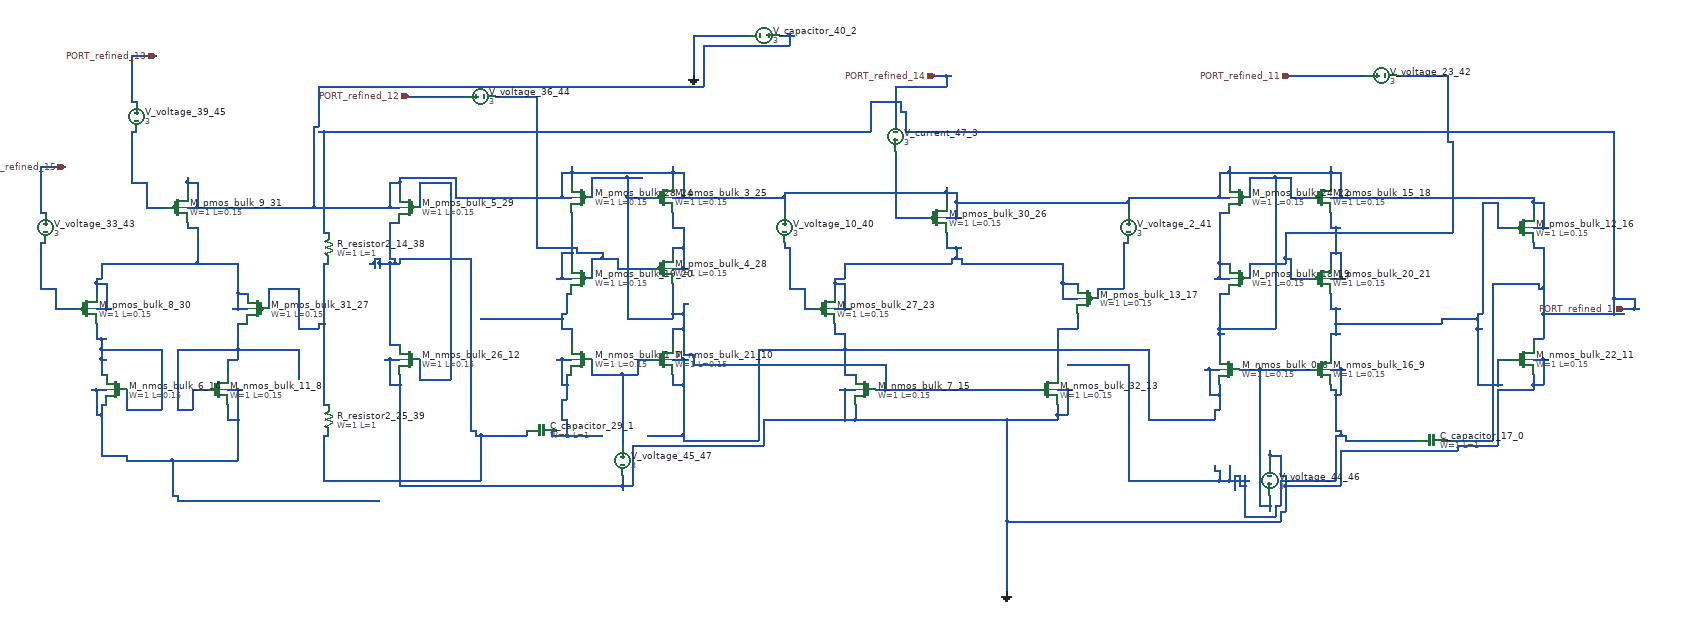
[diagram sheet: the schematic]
v {xschem version=3.4.8 file_version=1.2}
G {}
K {}
V {}
S {}
E {}
C {sky130_fd_pr/cap_mim_m3_1.sym} 2800 1020 1 0 {name="C_capacitor_17_0" model=cap_mim_m3_1 W=1 L=1 MF=1 spiceprefix=X}
C {sky130_fd_pr/cap_mim_m3_1.sym} 1040 1000 1 0 {name="C_capacitor_29_1" model=cap_mim_m3_1 W=1 L=1 MF=1 spiceprefix=X}
C {devices/vsource.sym} 1480 220 1 0 {name="V_capacitor_40_2" value=3 savecurrent=false}
C {devices/vsource.sym} 1740 420 2 0 {name="V_current_47_3" value=3 savecurrent=false}
C {devices/gnd.sym} 1960 1320 0 0 {name="l_gnd_37_4" lab="GND"}
C {devices/gnd.sym} 1340 300 0 0 {name="l_gnd_38_5" lab="GND"}
C {sky130_fd_pr/nfet_01v8.sym} 2400 880 0 1 {name="M_nmos_bulk_0_6"
W=1
L=0.15
nf=1 
mult=1
ad="expr('int((@nf + 1)/2) * @W / @nf * 0.29')"
pd="expr('2*int((@nf + 1)/2) * (@W / @nf + 0.29)')"
as="expr('int((@nf + 2)/2) * @W / @nf * 0.29')"
ps="expr('2*int((@nf + 2)/2) * (@W / @nf + 0.29)')"
nrd="expr('0.29 / @W ')" nrs="expr('0.29 / @W ')"
sa=0 sb=0 sd=0
model=nfet_01v8
spiceprefix=X
}
C {sky130_fd_pr/nfet_01v8.sym} 1120 860 0 1 {name="M_nmos_bulk_1_7"
W=1
L=0.15
nf=1 
mult=1
ad="expr('int((@nf + 1)/2) * @W / @nf * 0.29')"
pd="expr('2*int((@nf + 1)/2) * (@W / @nf + 0.29)')"
as="expr('int((@nf + 2)/2) * @W / @nf * 0.29')"
ps="expr('2*int((@nf + 2)/2) * (@W / @nf + 0.29)')"
nrd="expr('0.29 / @W ')" nrs="expr('0.29 / @W ')"
sa=0 sb=0 sd=0
model=nfet_01v8
spiceprefix=X
}
C {sky130_fd_pr/nfet_01v8.sym} 400 920 0 0 {name="M_nmos_bulk_11_8"
W=1
L=0.15
nf=1 
mult=1
ad="expr('int((@nf + 1)/2) * @W / @nf * 0.29')"
pd="expr('2*int((@nf + 1)/2) * (@W / @nf + 0.29)')"
as="expr('int((@nf + 2)/2) * @W / @nf * 0.29')"
ps="expr('2*int((@nf + 2)/2) * (@W / @nf + 0.29)')"
nrd="expr('0.29 / @W ')" nrs="expr('0.29 / @W ')"
sa=0 sb=0 sd=0
model=nfet_01v8
spiceprefix=X
}
C {sky130_fd_pr/nfet_01v8.sym} 2580 880 0 0 {name="M_nmos_bulk_16_9"
W=1
L=0.15
nf=1 
mult=1
ad="expr('int((@nf + 1)/2) * @W / @nf * 0.29')"
pd="expr('2*int((@nf + 1)/2) * (@W / @nf + 0.29)')"
as="expr('int((@nf + 2)/2) * @W / @nf * 0.29')"
ps="expr('2*int((@nf + 2)/2) * (@W / @nf + 0.29)')"
nrd="expr('0.29 / @W ')" nrs="expr('0.29 / @W ')"
sa=0 sb=0 sd=0
model=nfet_01v8
spiceprefix=X
}
C {sky130_fd_pr/nfet_01v8.sym} 1280 860 0 0 {name="M_nmos_bulk_21_10"
W=1
L=0.15
nf=1 
mult=1
ad="expr('int((@nf + 1)/2) * @W / @nf * 0.29')"
pd="expr('2*int((@nf + 1)/2) * (@W / @nf + 0.29)')"
as="expr('int((@nf + 2)/2) * @W / @nf * 0.29')"
ps="expr('2*int((@nf + 2)/2) * (@W / @nf + 0.29)')"
nrd="expr('0.29 / @W ')" nrs="expr('0.29 / @W ')"
sa=0 sb=0 sd=0
model=nfet_01v8
spiceprefix=X
}
C {sky130_fd_pr/nfet_01v8.sym} 2980 860 0 0 {name="M_nmos_bulk_22_11"
W=1
L=0.15
nf=1 
mult=1
ad="expr('int((@nf + 1)/2) * @W / @nf * 0.29')"
pd="expr('2*int((@nf + 1)/2) * (@W / @nf + 0.29)')"
as="expr('int((@nf + 2)/2) * @W / @nf * 0.29')"
ps="expr('2*int((@nf + 2)/2) * (@W / @nf + 0.29)')"
nrd="expr('0.29 / @W ')" nrs="expr('0.29 / @W ')"
sa=0 sb=0 sd=0
model=nfet_01v8
spiceprefix=X
}
C {sky130_fd_pr/nfet_01v8.sym} 780 860 0 1 {name="M_nmos_bulk_26_12"
W=1
L=0.15
nf=1 
mult=1
ad="expr('int((@nf + 1)/2) * @W / @nf * 0.29')"
pd="expr('2*int((@nf + 1)/2) * (@W / @nf + 0.29)')"
as="expr('int((@nf + 2)/2) * @W / @nf * 0.29')"
ps="expr('2*int((@nf + 2)/2) * (@W / @nf + 0.29)')"
nrd="expr('0.29 / @W ')" nrs="expr('0.29 / @W ')"
sa=0 sb=0 sd=0
model=nfet_01v8
spiceprefix=X
}
C {sky130_fd_pr/nfet_01v8.sym} 2040 920 0 0 {name="M_nmos_bulk_32_13"
W=1
L=0.15
nf=1 
mult=1
ad="expr('int((@nf + 1)/2) * @W / @nf * 0.29')"
pd="expr('2*int((@nf + 1)/2) * (@W / @nf + 0.29)')"
as="expr('int((@nf + 2)/2) * @W / @nf * 0.29')"
ps="expr('2*int((@nf + 2)/2) * (@W / @nf + 0.29)')"
nrd="expr('0.29 / @W ')" nrs="expr('0.29 / @W ')"
sa=0 sb=0 sd=0
model=nfet_01v8
spiceprefix=X
}
C {sky130_fd_pr/nfet_01v8.sym} 200 920 0 1 {name="M_nmos_bulk_6_14"
W=1
L=0.15
nf=1 
mult=1
ad="expr('int((@nf + 1)/2) * @W / @nf * 0.29')"
pd="expr('2*int((@nf + 1)/2) * (@W / @nf + 0.29)')"
as="expr('int((@nf + 2)/2) * @W / @nf * 0.29')"
ps="expr('2*int((@nf + 2)/2) * (@W / @nf + 0.29)')"
nrd="expr('0.29 / @W ')" nrs="expr('0.29 / @W ')"
sa=0 sb=0 sd=0
model=nfet_01v8
spiceprefix=X
}
C {sky130_fd_pr/nfet_01v8.sym} 1680 920 0 1 {name="M_nmos_bulk_7_15"
W=1
L=0.15
nf=1 
mult=1
ad="expr('int((@nf + 1)/2) * @W / @nf * 0.29')"
pd="expr('2*int((@nf + 1)/2) * (@W / @nf + 0.29)')"
as="expr('int((@nf + 2)/2) * @W / @nf * 0.29')"
ps="expr('2*int((@nf + 2)/2) * (@W / @nf + 0.29)')"
nrd="expr('0.29 / @W ')" nrs="expr('0.29 / @W ')"
sa=0 sb=0 sd=0
model=nfet_01v8
spiceprefix=X
}
C {sky130_fd_pr/pfet_01v8.sym} 2980 600 0 0 {name="M_pmos_bulk_12_16"
W=1
L=0.15
nf=1
mult=1
ad="expr('int((@nf + 1)/2) * @W / @nf * 0.29')"
pd="expr('2*int((@nf + 1)/2) * (@W / @nf + 0.29)')"
as="expr('int((@nf + 2)/2) * @W / @nf * 0.29')"
ps="expr('2*int((@nf + 2)/2) * (@W / @nf + 0.29)')"
nrd="expr('0.29 / @W ')" nrs="expr('0.29 / @W ')"
sa=0 sb=0 sd=0
model=pfet_01v8
spiceprefix=X
}
C {sky130_fd_pr/pfet_01v8.sym} 2120 740 0 1 {name="M_pmos_bulk_13_17"
W=1
L=0.15
nf=1
mult=1
ad="expr('int((@nf + 1)/2) * @W / @nf * 0.29')"
pd="expr('2*int((@nf + 1)/2) * (@W / @nf + 0.29)')"
as="expr('int((@nf + 2)/2) * @W / @nf * 0.29')"
ps="expr('2*int((@nf + 2)/2) * (@W / @nf + 0.29)')"
nrd="expr('0.29 / @W ')" nrs="expr('0.29 / @W ')"
sa=0 sb=0 sd=0
model=pfet_01v8
spiceprefix=X
}
C {sky130_fd_pr/pfet_01v8.sym} 2580 540 0 0 {name="M_pmos_bulk_15_18"
W=1
L=0.15
nf=1
mult=1
ad="expr('int((@nf + 1)/2) * @W / @nf * 0.29')"
pd="expr('2*int((@nf + 1)/2) * (@W / @nf + 0.29)')"
as="expr('int((@nf + 2)/2) * @W / @nf * 0.29')"
ps="expr('2*int((@nf + 2)/2) * (@W / @nf + 0.29)')"
nrd="expr('0.29 / @W ')" nrs="expr('0.29 / @W ')"
sa=0 sb=0 sd=0
model=pfet_01v8
spiceprefix=X
}
C {sky130_fd_pr/pfet_01v8.sym} 2420 700 0 1 {name="M_pmos_bulk_18_19"
W=1
L=0.15
nf=1
mult=1
ad="expr('int((@nf + 1)/2) * @W / @nf * 0.29')"
pd="expr('2*int((@nf + 1)/2) * (@W / @nf + 0.29)')"
as="expr('int((@nf + 2)/2) * @W / @nf * 0.29')"
ps="expr('2*int((@nf + 2)/2) * (@W / @nf + 0.29)')"
nrd="expr('0.29 / @W ')" nrs="expr('0.29 / @W ')"
sa=0 sb=0 sd=0
model=pfet_01v8
spiceprefix=X
}
C {sky130_fd_pr/pfet_01v8.sym} 1120 700 0 1 {name="M_pmos_bulk_19_20"
W=1
L=0.15
nf=1
mult=1
ad="expr('int((@nf + 1)/2) * @W / @nf * 0.29')"
pd="expr('2*int((@nf + 1)/2) * (@W / @nf + 0.29)')"
as="expr('int((@nf + 2)/2) * @W / @nf * 0.29')"
ps="expr('2*int((@nf + 2)/2) * (@W / @nf + 0.29)')"
nrd="expr('0.29 / @W ')" nrs="expr('0.29 / @W ')"
sa=0 sb=0 sd=0
model=pfet_01v8
spiceprefix=X
}
C {sky130_fd_pr/pfet_01v8.sym} 2580 700 0 0 {name="M_pmos_bulk_20_21"
W=1
L=0.15
nf=1
mult=1
ad="expr('int((@nf + 1)/2) * @W / @nf * 0.29')"
pd="expr('2*int((@nf + 1)/2) * (@W / @nf + 0.29)')"
as="expr('int((@nf + 2)/2) * @W / @nf * 0.29')"
ps="expr('2*int((@nf + 2)/2) * (@W / @nf + 0.29)')"
nrd="expr('0.29 / @W ')" nrs="expr('0.29 / @W ')"
sa=0 sb=0 sd=0
model=pfet_01v8
spiceprefix=X
}
C {sky130_fd_pr/pfet_01v8.sym} 2420 540 0 1 {name="M_pmos_bulk_24_22"
W=1
L=0.15
nf=1
mult=1
ad="expr('int((@nf + 1)/2) * @W / @nf * 0.29')"
pd="expr('2*int((@nf + 1)/2) * (@W / @nf + 0.29)')"
as="expr('int((@nf + 2)/2) * @W / @nf * 0.29')"
ps="expr('2*int((@nf + 2)/2) * (@W / @nf + 0.29)')"
nrd="expr('0.29 / @W ')" nrs="expr('0.29 / @W ')"
sa=0 sb=0 sd=0
model=pfet_01v8
spiceprefix=X
}
C {sky130_fd_pr/pfet_01v8.sym} 1600 760 0 0 {name="M_pmos_bulk_27_23"
W=1
L=0.15
nf=1
mult=1
ad="expr('int((@nf + 1)/2) * @W / @nf * 0.29')"
pd="expr('2*int((@nf + 1)/2) * (@W / @nf + 0.29)')"
as="expr('int((@nf + 2)/2) * @W / @nf * 0.29')"
ps="expr('2*int((@nf + 2)/2) * (@W / @nf + 0.29)')"
nrd="expr('0.29 / @W ')" nrs="expr('0.29 / @W ')"
sa=0 sb=0 sd=0
model=pfet_01v8
spiceprefix=X
}
C {sky130_fd_pr/pfet_01v8.sym} 1120 540 0 1 {name="M_pmos_bulk_28_24"
W=1
L=0.15
nf=1
mult=1
ad="expr('int((@nf + 1)/2) * @W / @nf * 0.29')"
pd="expr('2*int((@nf + 1)/2) * (@W / @nf + 0.29)')"
as="expr('int((@nf + 2)/2) * @W / @nf * 0.29')"
ps="expr('2*int((@nf + 2)/2) * (@W / @nf + 0.29)')"
nrd="expr('0.29 / @W ')" nrs="expr('0.29 / @W ')"
sa=0 sb=0 sd=0
model=pfet_01v8
spiceprefix=X
}
C {sky130_fd_pr/pfet_01v8.sym} 1280 540 0 0 {name="M_pmos_bulk_3_25"
W=1
L=0.15
nf=1
mult=1
ad="expr('int((@nf + 1)/2) * @W / @nf * 0.29')"
pd="expr('2*int((@nf + 1)/2) * (@W / @nf + 0.29)')"
as="expr('int((@nf + 2)/2) * @W / @nf * 0.29')"
ps="expr('2*int((@nf + 2)/2) * (@W / @nf + 0.29)')"
nrd="expr('0.29 / @W ')" nrs="expr('0.29 / @W ')"
sa=0 sb=0 sd=0
model=pfet_01v8
spiceprefix=X
}
C {sky130_fd_pr/pfet_01v8.sym} 1820 580 0 0 {name="M_pmos_bulk_30_26"
W=1
L=0.15
nf=1
mult=1
ad="expr('int((@nf + 1)/2) * @W / @nf * 0.29')"
pd="expr('2*int((@nf + 1)/2) * (@W / @nf + 0.29)')"
as="expr('int((@nf + 2)/2) * @W / @nf * 0.29')"
ps="expr('2*int((@nf + 2)/2) * (@W / @nf + 0.29)')"
nrd="expr('0.29 / @W ')" nrs="expr('0.29 / @W ')"
sa=0 sb=0 sd=0
model=pfet_01v8
spiceprefix=X
}
C {sky130_fd_pr/pfet_01v8.sym} 480 760 0 1 {name="M_pmos_bulk_31_27"
W=1
L=0.15
nf=1
mult=1
ad="expr('int((@nf + 1)/2) * @W / @nf * 0.29')"
pd="expr('2*int((@nf + 1)/2) * (@W / @nf + 0.29)')"
as="expr('int((@nf + 2)/2) * @W / @nf * 0.29')"
ps="expr('2*int((@nf + 2)/2) * (@W / @nf + 0.29)')"
nrd="expr('0.29 / @W ')" nrs="expr('0.29 / @W ')"
sa=0 sb=0 sd=0
model=pfet_01v8
spiceprefix=X
}
C {sky130_fd_pr/pfet_01v8.sym} 1280 680 0 0 {name="M_pmos_bulk_4_28"
W=1
L=0.15
nf=1
mult=1
ad="expr('int((@nf + 1)/2) * @W / @nf * 0.29')"
pd="expr('2*int((@nf + 1)/2) * (@W / @nf + 0.29)')"
as="expr('int((@nf + 2)/2) * @W / @nf * 0.29')"
ps="expr('2*int((@nf + 2)/2) * (@W / @nf + 0.29)')"
nrd="expr('0.29 / @W ')" nrs="expr('0.29 / @W ')"
sa=0 sb=0 sd=0
model=pfet_01v8
spiceprefix=X
}
C {sky130_fd_pr/pfet_01v8.sym} 780 560 0 1 {name="M_pmos_bulk_5_29"
W=1
L=0.15
nf=1
mult=1
ad="expr('int((@nf + 1)/2) * @W / @nf * 0.29')"
pd="expr('2*int((@nf + 1)/2) * (@W / @nf + 0.29)')"
as="expr('int((@nf + 2)/2) * @W / @nf * 0.29')"
ps="expr('2*int((@nf + 2)/2) * (@W / @nf + 0.29)')"
nrd="expr('0.29 / @W ')" nrs="expr('0.29 / @W ')"
sa=0 sb=0 sd=0
model=pfet_01v8
spiceprefix=X
}
C {sky130_fd_pr/pfet_01v8.sym} 140 760 0 0 {name="M_pmos_bulk_8_30"
W=1
L=0.15
nf=1
mult=1
ad="expr('int((@nf + 1)/2) * @W / @nf * 0.29')"
pd="expr('2*int((@nf + 1)/2) * (@W / @nf + 0.29)')"
as="expr('int((@nf + 2)/2) * @W / @nf * 0.29')"
ps="expr('2*int((@nf + 2)/2) * (@W / @nf + 0.29)')"
nrd="expr('0.29 / @W ')" nrs="expr('0.29 / @W ')"
sa=0 sb=0 sd=0
model=pfet_01v8
spiceprefix=X
}
C {sky130_fd_pr/pfet_01v8.sym} 320 560 0 0 {name="M_pmos_bulk_9_31"
W=1
L=0.15
nf=1
mult=1
ad="expr('int((@nf + 1)/2) * @W / @nf * 0.29')"
pd="expr('2*int((@nf + 1)/2) * (@W / @nf + 0.29)')"
as="expr('int((@nf + 2)/2) * @W / @nf * 0.29')"
ps="expr('2*int((@nf + 2)/2) * (@W / @nf + 0.29)')"
nrd="expr('0.29 / @W ')" nrs="expr('0.29 / @W ')"
sa=0 sb=0 sd=0
model=pfet_01v8
spiceprefix=X
}
C {devices/ipin.sym} 2520 300 0 0 {name="p_port_34_32" lab="PORT_refined_11"}
C {devices/ipin.sym} 780 340 0 0 {name="p_port_35_33" lab="PORT_refined_12"}
C {devices/ipin.sym} 280 260 0 0 {name="p_port_41_34" lab="PORT_refined_13"}
C {devices/ipin.sym} 3180 760 0 0 {name="p_port_42_35" lab="PORT_refined_1"}
C {devices/ipin.sym} 1820 300 0 0 {name="p_port_43_36" lab="PORT_refined_14"}
C {devices/ipin.sym} 100 480 0 0 {name="p_port_46_37" lab="PORT_refined_15"}
C {sky130_fd_pr/res_generic_po.sym} 620 640 2 0 {name="R_resistor2_14_38"
W=1
L=1
model=res_generic_po
spiceprefix=X
mult=1}
C {sky130_fd_pr/res_generic_po.sym} 620 980 2 0 {name="R_resistor2_25_39"
W=1
L=1
model=res_generic_po
spiceprefix=X
mult=1}
C {devices/vsource.sym} 1520 600 0 0 {name="V_voltage_10_40" value=3 savecurrent=false}
C {devices/vsource.sym} 2200 600 0 0 {name="V_voltage_2_41" value=3 savecurrent=false}
C {devices/vsource.sym} 2700 300 3 0 {name="V_voltage_23_42" value=3 savecurrent=false}
C {devices/vsource.sym} 60 600 0 0 {name="V_voltage_33_43" value=3 savecurrent=false}
C {devices/vsource.sym} 920 340 3 0 {name="V_voltage_36_44" value=3 savecurrent=false}
C {devices/vsource.sym} 240 380 0 0 {name="V_voltage_39_45" value=3 savecurrent=false}
C {devices/vsource.sym} 2480 1100 2 0 {name="V_voltage_44_46" value=3 savecurrent=false}
C {devices/vsource.sym} 1200 1060 0 0 {name="V_voltage_45_47" value=3 savecurrent=false}
N 2430 1170 2490 1170 {}
N 2490 1150 2500 1150 {}
N 2420 1110 2430 1110 {}
N 2200 1100 2380 1100 {}
N 2380 1100 2400 1100 {}
N 2400 1100 2410 1100 {}
N 2410 1100 2420 1100 {}
N 2420 1100 2430 1100 {}
N 2430 1100 2440 1100 {}
N 2500 1100 2610 1100 {}
N 2410 1090 2420 1090 {}
N 2370 1080 2380 1080 {}
N 2630 1020 2770 1020 {}
N 2610 1010 2620 1010 {}
N 2620 1010 2630 1010 {}
N 2610 1000 2620 1000 {}
N 2610 930 2620 930 {}
N 2600 920 2610 920 {}
N 2600 880 2620 880 {}
N 2620 880 2630 880 {}
N 2080 870 2200 870 {}
N 2200 1100 2200 870 {}
N 2370 1080 2370 1070 {}
N 2380 1100 2380 1080 {}
N 2400 1100 2400 1070 {}
N 2410 1120 2410 1100 {}
N 2410 1100 2410 1090 {}
N 2420 1110 2420 1100 {}
N 2420 1100 2420 1090 {}
N 2430 1170 2430 1110 {}
N 2430 1110 2430 1100 {}
N 2430 1100 2430 1090 {}
N 2490 1170 2490 1150 {}
N 2500 1150 2500 1100 {}
N 2600 920 2600 910 {}
N 2610 1100 2610 1010 {}
N 2610 1000 2610 930 {}
N 2610 930 2610 920 {}
N 2620 1010 2620 1000 {}
N 2620 930 2620 880 {}
N 2630 1020 2630 1010 {}
N 2820 1020 2830 1020 {}
N 2830 1020 2920 1020 {}
N 3000 820 3020 820 {}
N 3020 770 3160 770 {}
N 3160 770 3180 770 {}
N 3180 760 3200 760 {}
N 3200 760 3210 760 {}
N 3160 740 3200 740 {}
N 3010 720 3020 720 {}
N 2920 710 3010 710 {}
N 3000 640 3020 640 {}
N 610 610 620 610 {}
N 600 410 610 410 {}
N 610 410 1690 410 {}
N 1760 410 3160 410 {}
N 1750 370 1760 370 {}
N 1690 350 1750 350 {}
N 610 610 610 410 {}
N 1690 410 1690 350 {}
N 1750 370 1750 350 {}
N 1760 410 1760 370 {}
N 2920 1020 2920 710 {}
N 3000 830 3000 820 {}
N 3000 640 3000 630 {}
N 3010 720 3010 710 {}
N 3020 820 3020 770 {}
N 3020 770 3020 720 {}
N 3020 720 3020 640 {}
N 3160 770 3160 740 {}
N 3160 740 3160 410 {}
N 3200 760 3200 740 {}
N 260 560 300 560 {}
N 230 510 260 510 {}
N 230 410 240 410 {}
N 230 510 230 410 {}
N 260 560 260 510 {}
N 2520 300 2670 300 {}
N 770 340 780 340 {}
N 780 340 890 340 {}
N 230 350 240 350 {}
N 230 260 280 260 {}
N 230 350 230 260 {}
N 1740 320 1840 320 {}
N 1820 300 1840 300 {}
N 1840 300 1850 300 {}
N 1740 390 1740 320 {}
N 1840 320 1840 300 {}
N 50 570 60 570 {}
N 50 480 100 480 {}
N 50 570 50 480 {}
N 2380 810 2390 810 {}
N 2380 800 2490 800 {}
N 2380 730 2400 730 {}
N 2520 540 2560 540 {}
N 2440 500 2490 500 {}
N 2490 500 2520 500 {}
N 2380 850 2380 810 {}
N 2380 810 2380 800 {}
N 2380 800 2380 730 {}
N 2440 540 2440 500 {}
N 2490 800 2490 500 {}
N 2520 540 2520 500 {}
N 610 950 620 950 {}
N 560 800 600 800 {}
N 600 790 610 790 {}
N 500 720 560 720 {}
N 610 670 620 670 {}
N 500 760 500 720 {}
N 560 800 560 720 {}
N 600 800 600 790 {}
N 610 950 610 790 {}
N 610 790 610 670 {}
N 2140 720 2190 720 {}
N 2190 630 2200 630 {}
N 2140 740 2140 720 {}
N 2190 720 2190 630 {}
N 2520 700 2560 700 {}
N 2440 670 2510 670 {}
N 2510 660 2520 660 {}
N 2510 610 2840 610 {}
N 2830 430 2840 430 {}
N 2730 300 2830 300 {}
N 2440 700 2440 670 {}
N 2510 670 2510 660 {}
N 2510 660 2510 610 {}
N 2520 700 2520 660 {}
N 2830 430 2830 300 {}
N 2840 610 2840 430 {}
N 1320 1020 1470 1020 {}
N 1250 1010 1320 1010 {}
N 2240 980 2370 980 {}
N 2370 960 2380 960 {}
N 2360 930 2380 930 {}
N 1300 910 1320 910 {}
N 1640 890 1660 890 {}
N 2350 880 2360 880 {}
N 2360 880 2380 880 {}
N 1300 860 1320 860 {}
N 1320 860 1330 860 {}
N 1470 840 1640 840 {}
N 1640 840 2240 840 {}
N 1620 810 1640 810 {}
N 1300 910 1300 890 {}
N 1320 1020 1320 1010 {}
N 1320 1010 1320 910 {}
N 1320 910 1320 860 {}
N 1470 1020 1470 840 {}
N 1620 810 1620 790 {}
N 1640 890 1640 840 {}
N 1640 840 1640 810 {}
N 2240 980 2240 840 {}
N 2360 930 2360 880 {}
N 2370 980 2370 960 {}
N 2380 960 2380 930 {}
N 2380 930 2380 910 {}
N 2460 1150 2480 1150 {}
N 2420 880 2460 880 {}
N 2460 880 2560 880 {}
N 2460 1150 2460 880 {}
N 2480 1160 2480 1150 {}
N 2480 1150 2480 1130 {}
N 1140 890 1200 890 {}
N 1200 890 1230 890 {}
N 1230 860 1260 860 {}
N 1140 890 1140 860 {}
N 1200 1030 1200 890 {}
N 1230 890 1230 860 {}
N 320 1140 720 1140 {}
N 310 1130 320 1130 {}
N 220 1060 310 1060 {}
N 310 1060 440 1060 {}
N 170 1050 220 1050 {}
N 420 980 440 980 {}
N 160 970 170 970 {}
N 170 950 180 950 {}
N 150 920 160 920 {}
N 160 920 180 920 {}
N 420 920 440 920 {}
N 440 920 450 920 {}
N 160 970 160 920 {}
N 170 1050 170 970 {}
N 170 970 170 950 {}
N 220 1060 220 1050 {}
N 310 1130 310 1060 {}
N 320 1140 320 1130 {}
N 420 980 420 950 {}
N 440 1060 440 980 {}
N 440 980 440 920 {}
N 320 960 350 960 {}
N 350 920 380 920 {}
N 420 860 440 860 {}
N 320 840 440 840 {}
N 440 840 560 840 {}
N 440 790 460 790 {}
N 320 960 320 840 {}
N 350 960 350 920 {}
N 420 890 420 860 {}
N 440 860 440 840 {}
N 440 840 440 790 {}
N 560 900 560 840 {}
N 2890 910 2930 910 {}
N 2930 910 2940 910 {}
N 2930 860 2960 860 {}
N 2600 810 2610 810 {}
N 2610 810 2620 810 {}
N 2890 800 2900 800 {}
N 2610 790 2820 790 {}
N 2820 780 2890 780 {}
N 2890 770 2900 770 {}
N 2600 760 2610 760 {}
N 2610 760 2620 760 {}
N 2930 600 2960 600 {}
N 2900 550 2930 550 {}
N 2600 850 2600 810 {}
N 2600 760 2600 730 {}
N 2610 810 2610 790 {}
N 2610 790 2610 760 {}
N 2820 790 2820 780 {}
N 2890 910 2890 800 {}
N 2890 800 2890 780 {}
N 2890 780 2890 770 {}
N 2900 770 2900 550 {}
N 2930 910 2930 860 {}
N 2930 600 2930 550 {}
N 1060 1010 1090 1010 {}
N 1090 1010 1160 1010 {}
N 1060 1000 1070 1000 {}
N 1080 980 1090 980 {}
N 1080 940 1090 940 {}
N 1080 910 1090 910 {}
N 1090 890 1100 890 {}
N 1070 860 1080 860 {}
N 1080 860 1100 860 {}
N 1060 1010 1060 1000 {}
N 1080 980 1080 940 {}
N 1080 910 1080 860 {}
N 1090 1010 1090 980 {}
N 1090 940 1090 910 {}
N 1090 910 1090 890 {}
N 1960 1180 2500 1180 {}
N 2500 1160 2510 1160 {}
N 760 1110 1200 1110 {}
N 1200 1110 1220 1110 {}
N 2510 1110 2620 1110 {}
N 2500 1090 2510 1090 {}
N 2480 1050 2500 1050 {}
N 2620 1040 2850 1040 {}
N 1220 1030 1480 1030 {}
N 2850 1030 2930 1030 {}
N 1480 980 1640 980 {}
N 1640 980 1660 980 {}
N 1660 980 1960 980 {}
N 1960 980 2060 980 {}
N 2060 970 2080 970 {}
N 1630 920 1640 920 {}
N 1640 920 1660 920 {}
N 2060 920 2080 920 {}
N 2080 920 2090 920 {}
N 2930 920 3000 920 {}
N 740 910 760 910 {}
N 3000 910 3020 910 {}
N 730 860 740 860 {}
N 740 860 760 860 {}
N 3000 860 3020 860 {}
N 3020 860 3030 860 {}
N 1340 220 1450 220 {}
N 740 910 740 860 {}
N 760 1110 760 910 {}
N 760 910 760 890 {}
N 1200 1120 1200 1110 {}
N 1200 1110 1200 1090 {}
N 1220 1110 1220 1030 {}
N 1340 300 1340 220 {}
N 1480 1030 1480 980 {}
N 1640 980 1640 920 {}
N 1660 980 1660 950 {}
N 1960 1320 1960 1180 {}
N 1960 1180 1960 980 {}
N 2060 980 2060 970 {}
N 2060 970 2060 950 {}
N 2080 970 2080 920 {}
N 2480 1070 2480 1050 {}
N 2480 1050 2480 1040 {}
N 2500 1180 2500 1160 {}
N 2500 1090 2500 1050 {}
N 2510 1160 2510 1110 {}
N 2510 1110 2510 1090 {}
N 2620 1110 2620 1040 {}
N 2850 1040 2850 1030 {}
N 2930 1030 2930 920 {}
N 3000 920 3000 910 {}
N 3000 910 3000 890 {}
N 3020 910 3020 860 {}
N 2060 800 2100 800 {}
N 2060 890 2060 800 {}
N 2100 800 2100 770 {}
N 1620 760 1640 760 {}
N 1640 760 1650 760 {}
N 2070 740 2100 740 {}
N 1620 710 1640 710 {}
N 2070 710 2100 710 {}
N 1620 700 1640 700 {}
N 1640 670 1850 670 {}
N 1870 670 2070 670 {}
N 1850 660 1860 660 {}
N 1860 660 1870 660 {}
N 1840 640 1860 640 {}
N 1860 640 1870 640 {}
N 1620 730 1620 710 {}
N 1620 710 1620 700 {}
N 1640 760 1640 710 {}
N 1640 700 1640 670 {}
N 1840 640 1840 610 {}
N 1850 670 1850 660 {}
N 1860 660 1860 640 {}
N 1870 670 1870 660 {}
N 2070 740 2070 710 {}
N 2070 710 2070 670 {}
N 1740 580 1800 580 {}
N 1740 580 1740 450 {}
N 1700 920 1720 920 {}
N 1720 920 2020 920 {}
N 1340 870 1720 870 {}
N 1320 850 1340 850 {}
N 1300 800 1320 800 {}
N 1210 780 1300 780 {}
N 1300 770 1320 770 {}
N 1320 750 1330 750 {}
N 1210 540 1260 540 {}
N 1140 500 1210 500 {}
N 1210 500 1240 500 {}
N 1140 540 1140 500 {}
N 1210 780 1210 540 {}
N 1210 540 1210 500 {}
N 1300 830 1300 800 {}
N 1300 780 1300 770 {}
N 1300 770 1300 710 {}
N 1320 850 1320 800 {}
N 1320 800 1320 770 {}
N 1320 770 1320 750 {}
N 1340 870 1340 850 {}
N 1720 920 1720 870 {}
N 2600 700 2620 700 {}
N 2620 700 2630 700 {}
N 2600 650 2610 650 {}
N 2610 650 2620 650 {}
N 2600 600 2610 600 {}
N 2610 600 2620 600 {}
N 2600 670 2600 650 {}
N 2600 600 2600 570 {}
N 2610 650 2610 600 {}
N 2620 700 2620 650 {}
N 2370 700 2380 700 {}
N 2380 700 2400 700 {}
N 2380 670 2400 670 {}
N 2380 570 2400 570 {}
N 2380 700 2380 670 {}
N 2380 670 2380 570 {}
N 1070 700 1080 700 {}
N 1080 700 1100 700 {}
N 1080 650 1100 650 {}
N 1080 700 1080 650 {}
N 1100 670 1100 650 {}
N 1100 650 1100 570 {}
N 1080 800 1100 800 {}
N 920 780 1080 780 {}
N 1080 770 1090 770 {}
N 1090 730 1100 730 {}
N 1080 800 1080 780 {}
N 1080 780 1080 770 {}
N 1090 770 1090 730 {}
N 1100 830 1100 800 {}
N 1190 680 1260 680 {}
N 1140 660 1160 660 {}
N 1160 660 1190 660 {}
N 1110 650 1160 650 {}
N 1030 640 1110 640 {}
N 950 340 1030 340 {}
N 1030 640 1030 340 {}
N 1110 650 1110 640 {}
N 1140 700 1140 660 {}
N 1160 660 1160 650 {}
N 1190 680 1190 660 {}
N 1560 760 1580 760 {}
N 1530 720 1560 720 {}
N 1520 640 1530 640 {}
N 1520 640 1520 630 {}
N 1530 720 1530 640 {}
N 1560 760 1560 720 {}
N 1300 680 1320 680 {}
N 1320 680 1330 680 {}
N 1300 640 1320 640 {}
N 1300 600 1320 600 {}
N 1300 650 1300 640 {}
N 1300 600 1300 570 {}
N 1320 680 1320 640 {}
N 1320 640 1320 600 {}
N 3000 600 3020 600 {}
N 3020 600 3030 600 {}
N 1840 580 1860 580 {}
N 1860 580 1870 580 {}
N 340 560 360 560 {}
N 360 560 590 560 {}
N 590 560 740 560 {}
N 740 560 760 560 {}
N 1860 550 2200 550 {}
N 3000 550 3020 550 {}
N 870 540 1080 540 {}
N 1080 540 1100 540 {}
N 1300 540 1320 540 {}
N 1320 540 1520 540 {}
N 2200 540 2380 540 {}
N 2380 540 2400 540 {}
N 2600 540 2620 540 {}
N 2620 540 3000 540 {}
N 1520 530 1840 530 {}
N 1840 530 1860 530 {}
N 340 510 360 510 {}
N 740 510 760 510 {}
N 760 500 870 500 {}
N 1080 490 1100 490 {}
N 1100 490 1300 490 {}
N 1300 490 1320 490 {}
N 2380 490 2400 490 {}
N 2400 490 2600 490 {}
N 2600 490 2620 490 {}
N 590 400 600 400 {}
N 600 320 1360 320 {}
N 1360 240 1530 240 {}
N 1510 220 1530 220 {}
N 1530 220 1540 220 {}
N 340 530 340 510 {}
N 340 510 340 500 {}
N 360 560 360 510 {}
N 590 560 590 400 {}
N 600 400 600 320 {}
N 740 560 740 510 {}
N 760 530 760 510 {}
N 760 510 760 500 {}
N 870 540 870 500 {}
N 1080 540 1080 490 {}
N 1100 510 1100 490 {}
N 1100 490 1100 480 {}
N 1300 510 1300 490 {}
N 1300 490 1300 480 {}
N 1320 540 1320 490 {}
N 1360 320 1360 240 {}
N 1520 570 1520 540 {}
N 1520 540 1520 530 {}
N 1530 240 1530 220 {}
N 1840 550 1840 530 {}
N 1840 530 1840 520 {}
N 1860 580 1860 550 {}
N 1860 550 1860 530 {}
N 2200 570 2200 550 {}
N 2200 550 2200 540 {}
N 2380 540 2380 490 {}
N 2400 510 2400 490 {}
N 2400 490 2400 480 {}
N 2600 510 2600 490 {}
N 2600 490 2600 480 {}
N 2620 540 2620 490 {}
N 3000 570 3000 550 {}
N 3000 550 3000 540 {}
N 3020 600 3020 550 {}
N 610 1100 920 1100 {}
N 610 1010 620 1010 {}
N 910 1010 920 1010 {}
N 920 1010 1010 1010 {}
N 900 1000 910 1000 {}
N 740 830 760 830 {}
N 700 670 710 670 {}
N 720 670 740 670 {}
N 740 670 750 670 {}
N 750 670 760 670 {}
N 710 660 720 660 {}
N 740 660 750 660 {}
N 760 660 900 660 {}
N 740 590 760 590 {}
N 610 1100 610 1010 {}
N 710 680 710 670 {}
N 710 670 710 660 {}
N 720 680 720 670 {}
N 720 670 720 660 {}
N 740 830 740 670 {}
N 740 660 740 590 {}
N 750 670 750 660 {}
N 760 670 760 660 {}
N 900 1000 900 660 {}
N 910 1010 910 1000 {}
N 920 1100 920 1010 {}
N 1010 1010 1010 1000 {}
N 800 900 860 900 {}
N 800 510 860 510 {}
N 800 900 800 860 {}
N 800 560 800 510 {}
N 860 900 860 510 {}
N 160 760 180 760 {}
N 180 760 190 760 {}
N 430 760 440 760 {}
N 440 760 460 760 {}
N 440 730 460 730 {}
N 160 710 180 710 {}
N 160 700 170 700 {}
N 170 670 360 670 {}
N 360 670 440 670 {}
N 340 600 360 600 {}
N 160 730 160 710 {}
N 160 710 160 700 {}
N 170 700 170 670 {}
N 180 760 180 710 {}
N 340 600 340 590 {}
N 360 670 360 600 {}
N 440 760 440 730 {}
N 440 730 440 670 {}
N 220 960 290 960 {}
N 170 890 180 890 {}
N 170 860 180 860 {}
N 170 840 290 840 {}
N 160 820 170 820 {}
N 170 820 180 820 {}
N 160 820 160 790 {}
N 170 890 170 860 {}
N 170 860 170 840 {}
N 170 840 170 820 {}
N 220 960 220 920 {}
N 290 960 290 840 {}
N 80 760 120 760 {}
N 50 720 80 720 {}
N 50 630 60 630 {}
N 50 720 50 630 {}
N 80 760 80 720 {}
